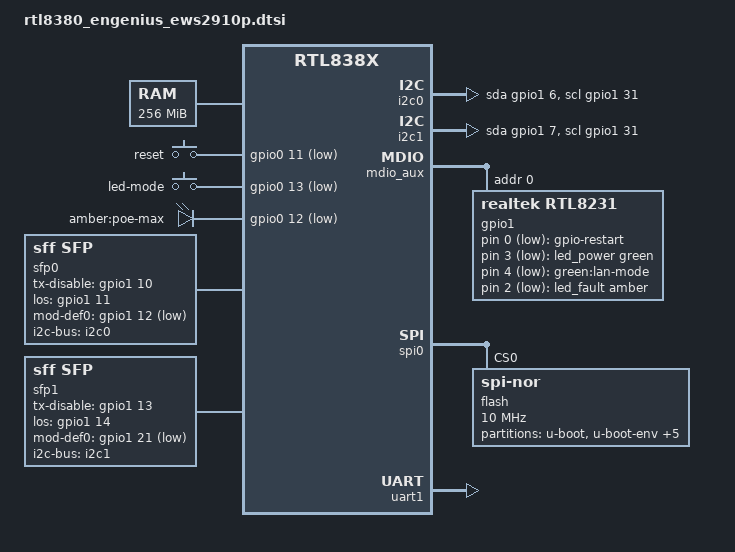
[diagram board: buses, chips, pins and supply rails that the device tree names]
// SPDX-License-Identifier: GPL-2.0-or-later

#include "rtl838x.dtsi"

#include <dt-bindings/input/input.h>
#include <dt-bindings/leds/common.h>
#include <dt-bindings/gpio/gpio.h>

/ {
	aliases {
		led-boot = &led_power;
		led-failsafe = &led_fault;
		led-running = &led_power;
		led-upgrade = &led_power;
	};

	memory@0 {
		device_type = "memory";
		reg = <0x0 0x10000000>;
	};

	keys {
		compatible = "gpio-keys";

		reset {
			label = "reset";
			gpios = <&gpio0 11 GPIO_ACTIVE_LOW>;
			linux,code = <KEY_RESTART>;
		};

		led_mode {
			label = "led-mode";
			gpios = <&gpio0 13 GPIO_ACTIVE_LOW>;
			linux,code = <BTN_0>;
		};
	};

	gpio-restart {
		compatible = "gpio-restart";
		gpios = <&gpio1 0 GPIO_ACTIVE_LOW>;
	};

	leds {
		compatible = "gpio-leds";

		led_power: led-0 {
			function = LED_FUNCTION_POWER;
			color = <LED_COLOR_ID_GREEN>;
			gpios = <&gpio1 3 GPIO_ACTIVE_LOW>;
		};

		led_lan_mode: led-1 {
			label = "green:lan-mode";
			gpios = <&gpio1 4 GPIO_ACTIVE_LOW>;
		};

		led_fault: led-2 {
			function = LED_FUNCTION_FAULT;
			color = <LED_COLOR_ID_AMBER>;
			gpios = <&gpio1 2 GPIO_ACTIVE_LOW>;
		};

		led_poe_max: led-3 {
			label = "amber:poe-max";
			gpios = <&gpio0 12 GPIO_ACTIVE_LOW>;
		};
	};

	i2c0: i2c-gpio-0 {
		compatible = "i2c-gpio";
		sda-gpios = <&gpio1 6 (GPIO_ACTIVE_HIGH | GPIO_OPEN_DRAIN)>;
		scl-gpios = <&gpio1 31 (GPIO_ACTIVE_HIGH | GPIO_OPEN_DRAIN)>;
		i2c-gpio,delay-us = <2>;
		#address-cells = <1>;
		#size-cells = <0>;
	};

	i2c1: i2c-gpio-1 {
		compatible = "i2c-gpio";
		sda-gpios = <&gpio1 7 (GPIO_ACTIVE_HIGH | GPIO_OPEN_DRAIN)>;
		scl-gpios = <&gpio1 31 (GPIO_ACTIVE_HIGH | GPIO_OPEN_DRAIN)>;
		i2c-gpio,delay-us = <2>;
		#address-cells = <1>;
		#size-cells = <0>;
	};

	sfp0: sfp-p9 {
		compatible = "sff,sfp";
		i2c-bus = <&i2c0>;
		tx-disable-gpio = <&gpio1 10 GPIO_ACTIVE_HIGH>;
		los-gpio = <&gpio1 11 GPIO_ACTIVE_HIGH>;
		mod-def0-gpio = <&gpio1 12 GPIO_ACTIVE_LOW>;
	};
	sfp1: sfp-p10 {
		compatible = "sff,sfp";
		i2c-bus = <&i2c1>;
		tx-disable-gpio = <&gpio1 13 GPIO_ACTIVE_HIGH>;
		los-gpio = <&gpio1 14 GPIO_ACTIVE_HIGH>;
		mod-def0-gpio = <&gpio1 21 GPIO_ACTIVE_LOW>;
	};
};

&mdio_aux {
	status = "okay";

	gpio1: expander@0 {
		compatible = "realtek,rtl8231";
		reg = <0>;

		gpio-controller;
		#gpio-cells = <2>;
		gpio-ranges = <&gpio1 0 0 37>;

		poe_enable {
			gpio-hog;
			gpios = <1 GPIO_ACTIVE_HIGH>;
			output-high;
			line-name = "poe-enable";
		};

		led-controller {
			compatible = "realtek,rtl8231-leds";
			status = "disabled";
		};
	};
};

&spi0 {
	status = "okay";

	flash@0 {
		compatible = "jedec,spi-nor";
		reg = <0>;
		spi-max-frequency = <10000000>;

		partitions {
			compatible = "fixed-partitions";
			#address-cells = <1>;
			#size-cells = <1>;

			partition@0 {
				label = "u-boot";
				reg = <0x0 0x80000>;
				read-only;
			};
			partition@80000 {
				label = "u-boot-env";
				reg = <0x80000 0x10000>;
				read-only;
			};
			partition@90000 {
				label = "u-boot-env2";
				reg = <0x90000 0x10000>;
			};
			partition@a0000 {
				label = "rootfs_data";
				reg = <0xa0000 0xd60000>;
			};
			partition@e00000 {
				label = "jffs2-log";
				reg = <0xe00000 0x200000>;
			};
			firmware_partition_1: partition@1000000 {
				label = "firmware";
				reg = <0x1000000 0x800000>;
			};
			firmware_partition_2: partition@1800000 {
				label = "firmware2";
				reg = <0x1800000 0x800000>;
			};
		};
	};
};

&mdio_bus0 {
	PHY_C22(8, 8)
	PHY_C22(9, 9)
	PHY_C22(10, 10)
	PHY_C22(11, 11)
	PHY_C22(12, 12)
	PHY_C22(13, 13)
	PHY_C22(14, 14)
	PHY_C22(15, 15)
};

&switch0 {
	ethernet-ports {
		#address-cells = <1>;
		#size-cells = <0>;

		SWITCH_PORT(8, 1, internal)
		SWITCH_PORT(9, 2, internal)
		SWITCH_PORT(10, 3, internal)
		SWITCH_PORT(11, 4, internal)
		SWITCH_PORT(12, 5, internal)
		SWITCH_PORT(13, 6, internal)
		SWITCH_PORT(14, 7, internal)
		SWITCH_PORT(15, 8, internal)

		port@24 {
			reg = <24>;
			label = "lan9";
			pcs-handle = <&serdes4 0>;
			phy-mode = "1000base-x";
			managed = "in-band-status";
			sfp = <&sfp0>;
		};

		port@26 {
			reg = <26>;
			label = "lan10";
			pcs-handle = <&serdes5 0>;
			phy-mode = "1000base-x";
			managed = "in-band-status";
			sfp = <&sfp1>;
		};

		port@28 {
			ethernet = <&ethernet0>;
			reg = <28>;
			phy-mode = "internal";

			fixed-link {
				speed = <1000>;
				full-duplex;
			};
		};
	};
};

&uart1 {
	status = "okay";

	/* PoE MCU; compatible and current-speed are set per variant */
	pse: ethernet-pse {
		pse-pis {
			#address-cells = <1>;
			#size-cells = <0>;

			PSE_PI(0)
			PSE_PI(1)
			PSE_PI(2)
			PSE_PI(3)
			PSE_PI(4)
			PSE_PI(5)
			PSE_PI(6)
			PSE_PI(7)
		};
	};
};

/* Copper ports lan1..lan8 (phy8..phy15) -> MCU PoE ports 0..7 */
&phy8  { pses = <&pse_pi0>; };
&phy9  { pses = <&pse_pi1>; };
&phy10 { pses = <&pse_pi2>; };
&phy11 { pses = <&pse_pi3>; };
&phy12 { pses = <&pse_pi4>; };
&phy13 { pses = <&pse_pi5>; };
&phy14 { pses = <&pse_pi6>; };
&phy15 { pses = <&pse_pi7>; };
